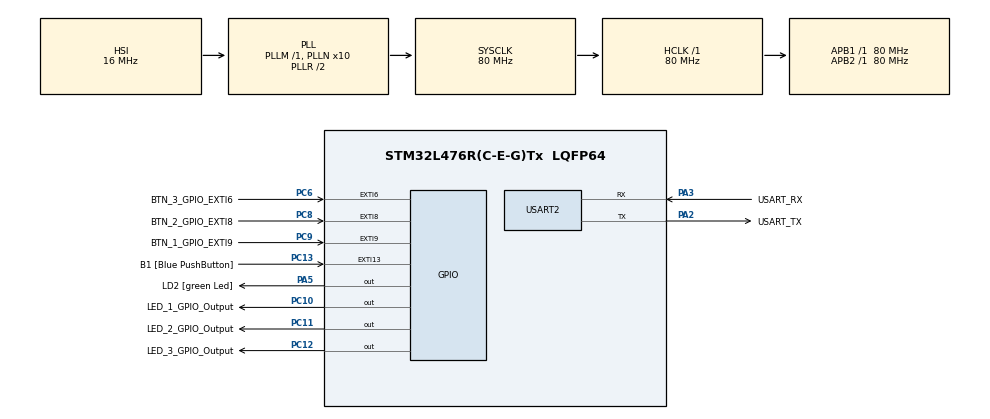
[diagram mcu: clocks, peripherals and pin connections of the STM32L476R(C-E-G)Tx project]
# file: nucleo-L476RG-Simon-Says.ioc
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Mcu.Family=STM32L4
Mcu.Name=STM32L476R(C-E-G)Tx
Mcu.Package=LQFP64
NVIC.EXTI9_5_IRQn=true\:0\:0\:false\:false\:true\:true\:true\:true
NVIC.PriorityGroup=NVIC_PRIORITYGROUP_4
PA13\ (JTMS-SWDIO).GPIO_Label=TMS
PA13\ (JTMS-SWDIO).Signal=SYS_JTMS-SWDIO
PA14\ (JTCK-SWCLK).GPIO_Label=TCK
PA14\ (JTCK-SWCLK).Signal=SYS_JTCK-SWCLK
PA2.GPIO_Label=USART_TX
PA2.GPIO_Mode=GPIO_MODE_AF_PP
PA2.GPIO_PuPd=GPIO_NOPULL
PA2.GPIO_Speed=GPIO_SPEED_FREQ_VERY_HIGH
PA2.Mode=Asynchronous
PA2.Signal=USART2_TX
PA3.GPIO_Label=USART_RX
PA3.GPIO_Mode=GPIO_MODE_AF_PP
PA3.GPIO_PuPd=GPIO_NOPULL
PA3.GPIO_Speed=GPIO_SPEED_FREQ_VERY_HIGH
PA3.Mode=Asynchronous
PA3.Signal=USART2_RX
PA5.GPIO_Label=LD2 [green Led]
PA5.GPIO_ModeDefaultOutputPP=GPIO_MODE_OUTPUT_PP
PA5.GPIO_PuPd=GPIO_NOPULL
PA5.GPIO_Speed=GPIO_SPEED_FREQ_LOW
PA5.Signal=GPIO_Output
PB3\ (JTDO-TRACESWO).GPIO_Label=SWO
PB3\ (JTDO-TRACESWO).Signal=SYS_JTDO-SWO
PC10.GPIO_Label=LED_1_GPIO_Output
PC10.Signal=GPIO_Output
PC11.GPIO_Label=LED_2_GPIO_Output
PC11.Signal=GPIO_Output
PC12.GPIO_Label=LED_3_GPIO_Output
PC12.Signal=GPIO_Output
PC13.GPIO_Label=B1 [Blue PushButton]
PC13.GPIO_ModeDefaultEXTI=GPIO_MODE_IT_FALLING
PC13.GPIO_PuPd=GPIO_NOPULL
PC13.Signal=GPXTI13
PC14-OSC32_IN\ (PC14).Signal=RCC_OSC32_IN
PC15-OSC32_OUT\ (PC15).Signal=RCC_OSC32_OUT
PC6.GPIO_Label=BTN_3_GPIO_EXTI6
PC6.GPIO_PuPd=GPIO_PULLUP
PC6.Signal=GPXTI6
PC8.GPIO_Label=BTN_2_GPIO_EXTI8
PC8.GPIO_PuPd=GPIO_PULLUP
PC8.Signal=GPXTI8
PC9.GPIO_Label=BTN_1_GPIO_EXTI9
PC9.GPIO_ModeDefaultEXTI=GPIO_MODE_IT_RISING
PC9.GPIO_PuPd=GPIO_PULLUP
PC9.Signal=GPXTI9
PH0-OSC_IN\ (PH0).Signal=RCC_OSC_IN
PH1-OSC_OUT\ (PH1).Signal=RCC_OSC_OUT
ProjectManager.HeapSize=0x200
ProjectManager.StackSize=0x400
ProjectManager.TargetToolchain=STM32CubeIDE
RCC.ADCFreq_Value=64000000
RCC.AHBFreq_Value=80000000
RCC.APB1Freq_Value=80000000
RCC.APB1TimFreq_Value=80000000
RCC.APB2Freq_Value=80000000
RCC.APB2TimFreq_Value=80000000
RCC.CK48CLockSelection=RCC_USBCLKSOURCE_MSI
RCC.CortexFreq_Value=80000000
RCC.HCLKFreq_Value=80000000
RCC.HSE_VALUE=8000000
RCC.HSI_VALUE=16000000
RCC.LSE_VALUE=32768
RCC.MSI_VALUE=4000000
RCC.PLLN=10
RCC.PLLSAI1Q=RCC_PLLQ_DIV4
RCC.PLLSourceVirtual=RCC_PLLSOURCE_HSI
RCC.PREFETCH_ENABLE=1
RCC.SYSCLKFreq_VALUE=80000000
RCC.SYSCLKSource=RCC_SYSCLKSOURCE_PLLCLK
RCC.USBFreq_Value=4000000
RCC.VCOOutputFreq_Value=160000000
USART2.VirtualMode-Asynchronous=VM_ASYNC
VP_RNG_VS_RNG.Mode=RNG_Activate
board=NUCLEO-L476RG

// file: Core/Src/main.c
/* USER CODE BEGIN Header */
/**
  ******************************************************************************
  * @file           : main.c
  * @brief          : Main program body
  ******************************************************************************
  * @attention
  *
  * Copyright (c) 2026 STMicroelectronics.
  * All rights reserved.
  *
  * This software is licensed under terms that can be found in the LICENSE file
  * in the root directory of this software component.
  * If no LICENSE file comes with this software, it is provided AS-IS.
  *
  ******************************************************************************
  */
/* USER CODE END Header */
#include "main.h"

/* USER CODE BEGIN Includes */
#include "stdio.h"
#include "string.h"
#include "stdlib.h"
/* USER CODE END Includes */

RNG_HandleTypeDef hrng;

UART_HandleTypeDef huart2;

/* USER CODE BEGIN PV */

#define SEQUENCE_MAX_LENGTH 50
#define DEBOUNCE_DELAY_MS   150

typedef enum {
    STATE_MENU,
    STATE_SHOW_SEQUENCE,
    STATE_PLAYER_INPUT,
    STATE_GAME_OVER
} GameState_t;

volatile GameState_t game_state = STATE_MENU;

uint8_t sequence[SEQUENCE_MAX_LENGTH];
uint8_t current_level = 0;
uint8_t sequence_length = 0;
uint8_t player_check_index = 0;
uint32_t random32bit;
volatile uint8_t button_pressed_flag = 0;
volatile uint8_t last_pressed_button = 0;
/* USER CODE END PV */

void SystemClock_Config(void);
static void MX_GPIO_Init(void);
static void MX_USART2_UART_Init(void);
static void MX_RNG_Init(void);

/* USER CODE BEGIN 0 */
void all_leds_on(void){
	HAL_GPIO_WritePin(LED_1_GPIO_Output_GPIO_Port, LED_1_GPIO_Output_Pin, GPIO_PIN_SET);
	HAL_GPIO_WritePin(LED_2_GPIO_Output_GPIO_Port, LED_2_GPIO_Output_Pin, GPIO_PIN_SET);
	HAL_GPIO_WritePin(LED_3_GPIO_Output_GPIO_Port, LED_3_GPIO_Output_Pin, GPIO_PIN_SET);
}
void all_leds_off(void){
	HAL_GPIO_WritePin(LED_1_GPIO_Output_GPIO_Port, LED_1_GPIO_Output_Pin, GPIO_PIN_RESET);
	HAL_GPIO_WritePin(LED_2_GPIO_Output_GPIO_Port, LED_2_GPIO_Output_Pin, GPIO_PIN_RESET);
	HAL_GPIO_WritePin(LED_3_GPIO_Output_GPIO_Port, LED_3_GPIO_Output_Pin, GPIO_PIN_RESET);
}
void turn_led_on(uint8_t led_num) {
    if (led_num == 0)      	HAL_GPIO_WritePin(LED_1_GPIO_Output_GPIO_Port, LED_1_GPIO_Output_Pin, GPIO_PIN_SET);
    else if (led_num == 1) 	HAL_GPIO_WritePin(LED_2_GPIO_Output_GPIO_Port, LED_2_GPIO_Output_Pin, GPIO_PIN_SET);
    else if (led_num == 2) 	HAL_GPIO_WritePin(LED_3_GPIO_Output_GPIO_Port, LED_3_GPIO_Output_Pin, GPIO_PIN_SET);

}
void error_indicators_on(void) {
    HAL_GPIO_WritePin(GPIOB, ERR_LED_GPIO_Output_Pin | ERR_BUZZER_GPIO_Output_Pin, GPIO_PIN_SET);
}

void error_indicators_off(void) {
    HAL_GPIO_WritePin(GPIOB, ERR_LED_GPIO_Output_Pin | ERR_BUZZER_GPIO_Output_Pin, GPIO_PIN_RESET);
}
void play_error_blink(void) {
    for (int i = 0; i < 4; i++) {
        all_leds_on();
        error_indicators_on();
        HAL_Delay(150);
        all_leds_off();
        error_indicators_off();
        HAL_Delay(150);
    }
}

void UART_Print(const char *str) {
    HAL_UART_Transmit(&huart2, (uint8_t *)str, strlen(str), HAL_MAX_DELAY);
}
void generate_next_level(void) {
    current_level++;
    sequence_length = current_level + 1;

    if (HAL_RNG_GenerateRandomNumber(&hrng, &random32bit) == HAL_OK) {
        sequence[sequence_length - 1] = (uint8_t)(random32bit % 3);
    } else {
        sequence[sequence_length - 1] = rand() % 3;
    }
}
void play_sequence(void) {
    char buffer[50];
    snprintf(buffer, sizeof(buffer), "\r\n--- LEVEL %u ---\r\nWatch the LEDs closely...\r\n", current_level);
    UART_Print(buffer);
    HAL_Delay(1000);

    uint32_t flash_delay = 800 - (current_level * 50);
    if (flash_delay < 200) flash_delay = 200; // Speed floor

    for (uint8_t i = 0; i < sequence_length; i++) {
        turn_led_on(sequence[i]);
        HAL_Delay(flash_delay);
        all_leds_off();
        HAL_Delay(flash_delay / 2); // Small gap between consecutive identical flashes
    }
    UART_Print("Your turn! Repeat the pattern...\r\n");
    player_check_index = 0;
    game_state = STATE_PLAYER_INPUT;
}
/* USER CODE END 0 */

int main(void)
{

  /* MCU Configuration--------------------------------------------------------*/

  /* Reset of all peripherals, Initializes the Flash interface and the Systick. */
  HAL_Init();

  /* Configure the system clock */
  SystemClock_Config();

  /* Initialize all configured peripherals */
  MX_GPIO_Init();
  MX_USART2_UART_Init();
  MX_RNG_Init();
  /* USER CODE BEGIN 2 */
    UART_Print("\r\n=========================\r\n");
    UART_Print("   WELCOME TO SIMON SAYS   \r\n");
    UART_Print("=========================\r\n");
    UART_Print("Press ANY button to start playing.\r\n");

    game_state = STATE_MENU;
  /* USER CODE END 2 */

  /* Infinite loop */
  /* USER CODE BEGIN WHILE */
 while (1)
  {

      if (button_pressed_flag) {
          uint8_t pressed = last_pressed_button;

          if (game_state == STATE_MENU) {
              button_pressed_flag = 0;
              turn_led_on(pressed);
              HAL_Delay(150);
              all_leds_off();

              srand(HAL_GetTick());
              current_level = 0;
              game_state = STATE_SHOW_SEQUENCE;
          }

          else if (game_state == STATE_GAME_OVER) {
              button_pressed_flag = 0;
              turn_led_on(pressed);
              HAL_Delay(150);
              all_leds_off();
              UART_Print("\r\n=== MAIN MENU ===\r\nPress ANY button to start a new game.\r\n");
              game_state = STATE_MENU;
          }

          else if (game_state == STATE_PLAYER_INPUT) {
              button_pressed_flag = 0;
              turn_led_on(pressed);
              HAL_Delay(200);
              all_leds_off();

              if (pressed == sequence[player_check_index]) {
                  player_check_index++;

                  if (player_check_index >= sequence_length) {
                      UART_Print("✨ Correct!\r\n");
                      HAL_Delay(500);
                      game_state = STATE_SHOW_SEQUENCE;
                  }
              } else {
                  char final_score_msg[128];
                  snprintf(final_score_msg, sizeof(final_score_msg),
                           "\r\n❌ WRONG BUTTON! Game Over.\r\nYou reached Level %u.\r\nPress ANY button to return to menu.\r\n",
                           current_level);
                  UART_Print(final_score_msg);

                  play_error_blink();
                  game_state = STATE_GAME_OVER;
              }
          }
      }

      else if (game_state == STATE_SHOW_SEQUENCE) {
          generate_next_level();
          play_sequence();
      }

      HAL_Delay(10);
  }
    /* USER CODE END WHILE */

  }

void SystemClock_Config(void)
{
  RCC_OscInitTypeDef RCC_OscInitStruct = {0};
  RCC_ClkInitTypeDef RCC_ClkInitStruct = {0};

  /** Configure the main internal regulator output voltage
  */
  if (HAL_PWREx_ControlVoltageScaling(PWR_REGULATOR_VOLTAGE_SCALE1) != HAL_OK)
  {
    Error_Handler();
  }

  /** Initializes the RCC Oscillators according to the specified parameters
  * in the RCC_OscInitTypeDef structure.
  */
  RCC_OscInitStruct.OscillatorType = RCC_OSCILLATORTYPE_HSI|RCC_OSCILLATORTYPE_MSI;
  RCC_OscInitStruct.HSIState = RCC_HSI_ON;
  RCC_OscInitStruct.HSICalibrationValue = RCC_HSICALIBRATION_DEFAULT;
  RCC_OscInitStruct.MSIState = RCC_MSI_ON;
  RCC_OscInitStruct.MSICalibrationValue = 0;
  RCC_OscInitStruct.MSIClockRange = RCC_MSIRANGE_6;
  RCC_OscInitStruct.PLL.PLLState = RCC_PLL_ON;
  RCC_OscInitStruct.PLL.PLLSource = RCC_PLLSOURCE_HSI;
  RCC_OscInitStruct.PLL.PLLM = 1;
  RCC_OscInitStruct.PLL.PLLN = 10;
  RCC_OscInitStruct.PLL.PLLP = RCC_PLLP_DIV7;
  RCC_OscInitStruct.PLL.PLLQ = RCC_PLLQ_DIV2;
  RCC_OscInitStruct.PLL.PLLR = RCC_PLLR_DIV2;
  if (HAL_RCC_OscConfig(&RCC_OscInitStruct) != HAL_OK)
  {
    Error_Handler();
  }

  /** Initializes the CPU, AHB and APB buses clocks
  */
  RCC_ClkInitStruct.ClockType = RCC_CLOCKTYPE_HCLK|RCC_CLOCKTYPE_SYSCLK
                              |RCC_CLOCKTYPE_PCLK1|RCC_CLOCKTYPE_PCLK2;
  RCC_ClkInitStruct.SYSCLKSource = RCC_SYSCLKSOURCE_PLLCLK;
  RCC_ClkInitStruct.AHBCLKDivider = RCC_SYSCLK_DIV1;
  RCC_ClkInitStruct.APB1CLKDivider = RCC_HCLK_DIV1;
  RCC_ClkInitStruct.APB2CLKDivider = RCC_HCLK_DIV1;

  if (HAL_RCC_ClockConfig(&RCC_ClkInitStruct, FLASH_LATENCY_4) != HAL_OK)
  {
    Error_Handler();
  }
}

static void MX_RNG_Init(void)
{

  hrng.Instance = RNG;
  if (HAL_RNG_Init(&hrng) != HAL_OK)
  {
    Error_Handler();
  }

}

static void MX_USART2_UART_Init(void)
{

  huart2.Instance = USART2;
  huart2.Init.BaudRate = 115200;
  huart2.Init.WordLength = UART_WORDLENGTH_8B;
  huart2.Init.StopBits = UART_STOPBITS_1;
  huart2.Init.Parity = UART_PARITY_NONE;
  huart2.Init.Mode = UART_MODE_TX_RX;
  huart2.Init.HwFlowCtl = UART_HWCONTROL_NONE;
  huart2.Init.OverSampling = UART_OVERSAMPLING_16;
  huart2.Init.OneBitSampling = UART_ONE_BIT_SAMPLE_DISABLE;
  huart2.AdvancedInit.AdvFeatureInit = UART_ADVFEATURE_NO_INIT;
  if (HAL_UART_Init(&huart2) != HAL_OK)
  {
    Error_Handler();
  }

}

static void MX_GPIO_Init(void)
{
  GPIO_InitTypeDef GPIO_InitStruct = {0};

  /* GPIO Ports Clock Enable */
  __HAL_RCC_GPIOC_CLK_ENABLE();
  __HAL_RCC_GPIOH_CLK_ENABLE();
  __HAL_RCC_GPIOA_CLK_ENABLE();
  __HAL_RCC_GPIOB_CLK_ENABLE();

  /*Configure GPIO pin Output Level */
  HAL_GPIO_WritePin(GPIOB, ERR_LED_GPIO_Output_Pin|ERR_BUZZER_GPIO_Output_Pin, GPIO_PIN_RESET);

  /*Configure GPIO pin Output Level */
  HAL_GPIO_WritePin(GPIOC, LED_1_GPIO_Output_Pin|LED_2_GPIO_Output_Pin|LED_3_GPIO_Output_Pin, GPIO_PIN_RESET);

  /*Configure GPIO pins : ERR_LED_GPIO_Output_Pin ERR_BUZZER_GPIO_Output_Pin */
  GPIO_InitStruct.Pin = ERR_LED_GPIO_Output_Pin|ERR_BUZZER_GPIO_Output_Pin;
  GPIO_InitStruct.Mode = GPIO_MODE_OUTPUT_PP;
  GPIO_InitStruct.Pull = GPIO_NOPULL;
  GPIO_InitStruct.Speed = GPIO_SPEED_FREQ_LOW;
  HAL_GPIO_Init(GPIOB, &GPIO_InitStruct);

  /*Configure GPIO pins : BTN_3_GPIO_EXTI6_Pin BTN_2_GPIO_EXTI8_Pin BTN_1_GPIO_EXTI9_Pin */
  GPIO_InitStruct.Pin = BTN_3_GPIO_EXTI6_Pin|BTN_2_GPIO_EXTI8_Pin|BTN_1_GPIO_EXTI9_Pin;
  GPIO_InitStruct.Mode = GPIO_MODE_IT_RISING;
  GPIO_InitStruct.Pull = GPIO_PULLUP;
  HAL_GPIO_Init(GPIOC, &GPIO_InitStruct);

  /*Configure GPIO pins : LED_1_GPIO_Output_Pin LED_2_GPIO_Output_Pin LED_3_GPIO_Output_Pin */
  GPIO_InitStruct.Pin = LED_1_GPIO_Output_Pin|LED_2_GPIO_Output_Pin|LED_3_GPIO_Output_Pin;
  GPIO_InitStruct.Mode = GPIO_MODE_OUTPUT_PP;
  GPIO_InitStruct.Pull = GPIO_NOPULL;
  GPIO_InitStruct.Speed = GPIO_SPEED_FREQ_LOW;
  HAL_GPIO_Init(GPIOC, &GPIO_InitStruct);

  /* EXTI interrupt init*/
  HAL_NVIC_SetPriority(EXTI9_5_IRQn, 0, 0);
  HAL_NVIC_EnableIRQ(EXTI9_5_IRQn);

}

/* USER CODE BEGIN 4 */
void HAL_GPIO_EXTI_Callback(uint16_t GPIO_Pin) {
    static uint32_t last_interrupt_time = 0;
    uint32_t current_time = HAL_GetTick();

    // Debounce check
    if ((current_time - last_interrupt_time) < DEBOUNCE_DELAY_MS) {
        return;
    }
    last_interrupt_time = current_time;

    // Identify which pin was pressed and set the flag
    if (GPIO_Pin == BTN_1_GPIO_EXTI9_Pin) {
        last_pressed_button = 0;
        button_pressed_flag = 1;
    } else if (GPIO_Pin == BTN_2_GPIO_EXTI8_Pin) {
        last_pressed_button = 1;
        button_pressed_flag = 1;
    } else if (GPIO_Pin == BTN_3_GPIO_EXTI6_Pin) {
        last_pressed_button = 2;
        button_pressed_flag = 1;
    }
}
/* USER CODE END 4 */

void Error_Handler(void)
{
  __disable_irq();
  while (1)
  {
  }
}
